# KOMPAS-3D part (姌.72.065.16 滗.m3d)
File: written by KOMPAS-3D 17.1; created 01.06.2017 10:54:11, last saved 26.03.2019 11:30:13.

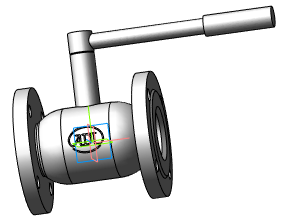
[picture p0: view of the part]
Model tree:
1. Операция без истории:2  (labels: Сталь 20  ГОСТ 1050-88)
